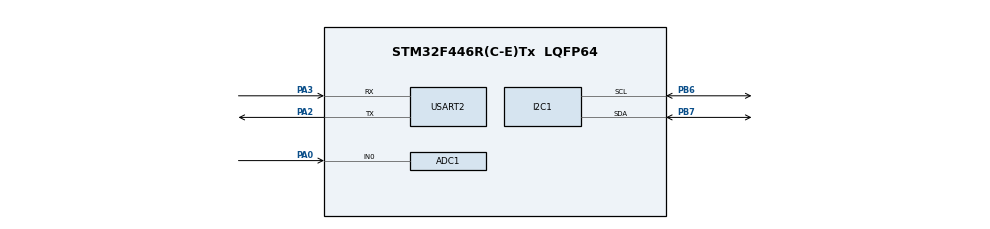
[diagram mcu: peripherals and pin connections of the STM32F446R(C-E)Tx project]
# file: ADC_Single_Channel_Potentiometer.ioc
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ADC1.Channel-0\#ChannelRegularConversion=ADC_CHANNEL_0
ADC1.ClockPrescaler=ADC_CLOCK_SYNC_PCLK_DIV4
ADC1.ContinuousConvMode=ENABLE
ADC1.NbrOfConversion=1
ADC1.NbrOfConversionFlag=1
ADC1.Rank-0\#ChannelRegularConversion=1
ADC1.SamplingTime-0\#ChannelRegularConversion=ADC_SAMPLETIME_3CYCLES
ADC1.master=1
FREERTOS.Tasks01=OLEDTask,24,128,StartTask01,Default,NULL,Dynamic,NULL,NULL;VoltageTask,24,128,StartTask02,Default,NULL,Dynamic,NULL,NULL
FREERTOS.configUSE_NEWLIB_REENTRANT=1
I2C1.I2C_Mode=I2C_Fast
Mcu.Family=STM32F4
Mcu.Name=STM32F446R(C-E)Tx
Mcu.Package=LQFP64
NVIC.PriorityGroup=NVIC_PRIORITYGROUP_4
NVIC.TIM1_UP_TIM10_IRQn=true\:15\:0\:false\:false\:true\:false\:false\:true\:true
NVIC.TimeBase=TIM1_UP_TIM10_IRQn
NVIC.TimeBaseIP=TIM1
PA0-WKUP.Signal=ADCx_IN0
PA13.Mode=Serial_Wire
PA13.Signal=SYS_JTMS-SWDIO
PA14.Mode=Serial_Wire
PA14.Signal=SYS_JTCK-SWCLK
PA2.Mode=Asynchronous
PA2.Signal=USART2_TX
PA3.Mode=Asynchronous
PA3.Signal=USART2_RX
PB6.Mode=I2C
PB6.Signal=I2C1_SCL
PB7.Mode=I2C
PB7.Signal=I2C1_SDA
PC14-OSC32_IN.Mode=LSE-External-Oscillator
PC14-OSC32_IN.Signal=RCC_OSC32_IN
PC15-OSC32_OUT.Mode=LSE-External-Oscillator
PC15-OSC32_OUT.Signal=RCC_OSC32_OUT
PH0-OSC_IN.Mode=HSE-External-Clock-Source
PH0-OSC_IN.Signal=RCC_OSC_IN
PH1-OSC_OUT.Mode=HSE-External-Clock-Source
PH1-OSC_OUT.Signal=RCC_OSC_OUT
ProjectManager.HeapSize=0x200
ProjectManager.StackSize=0x400
ProjectManager.TargetToolchain=STM32CubeIDE
RCC.48MHZClocksFreq_Value=84000000
RCC.AHBFreq_Value=64000000
RCC.APB1CLKDivider=RCC_HCLK_DIV2
RCC.APB1Freq_Value=32000000
RCC.APB1TimFreq_Value=64000000
RCC.APB2Freq_Value=64000000
RCC.APB2TimFreq_Value=64000000
RCC.CortexFreq_Value=64000000
RCC.FLatency-AdvancedSettings=FLASH_LATENCY_2
RCC.HCLKFreq_Value=64000000
RCC.HSE_VALUE=8000000
RCC.HSI_VALUE=16000000
RCC.PLLM=8
RCC.PLLN=64
RCC.SYSCLKFreq_VALUE=64000000
RCC.SYSCLKSource=RCC_SYSCLKSOURCE_PLLCLK
RCC.USBFreq_Value=64000000
RCC.VCOOutputFreq_Value=128000000
SH.ADCx_IN0.0=ADC1_IN0,IN0
USART2.VirtualMode=VM_ASYNC
VP_FREERTOS_VS_CMSIS_V2.Mode=CMSIS_V2
VP_SYS_VS_tim1.Mode=TIM1
board=NUCLEO-F446RE

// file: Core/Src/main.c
/* USER CODE BEGIN Header */
/**
  ******************************************************************************
  * @file           : main.c
  * @brief          : Main program body
  ******************************************************************************
  * @attention
  *
  * Copyright (c) 2024 STMicroelectronics.
  * All rights reserved.
  *
  * This software is licensed under terms that can be found in the LICENSE file
  * in the root directory of this software component.
  * If no LICENSE file comes with this software, it is provided AS-IS.
  *
  ******************************************************************************
  */
/* USER CODE END Header */
#include "main.h"
#include "cmsis_os.h"

/* USER CODE BEGIN Includes */
#include "task.h"
#include "stdio.h"
#include "string.h"
#include "fonts.h"
#include "ssd1306.h"
#include "semphr.h"

/* USER CODE END Includes */

ADC_HandleTypeDef hadc1;

I2C_HandleTypeDef hi2c1;

UART_HandleTypeDef huart2;

/* Definitions for adcTask */
osThreadId_t adcTaskHandle;
const osThreadAttr_t adcTask_attributes = {
  .name = "adcTask",
  .stack_size = 128 * 4,
  .priority = (osPriority_t) osPriorityNormal,
};
/* Definitions for oledTask */
osThreadId_t oledTaskHandle;
const osThreadAttr_t oledTask_attributes = {
  .name = "oledTask",
  .stack_size = 128 * 4,
  .priority = (osPriority_t) osPriorityNormal,
};

//Declare semaphore variables
SemaphoreHandle_t xBinarySemaphore1;
SemaphoreHandle_t xBinarySemaphore2;

void SystemClock_Config(void);
static void MX_GPIO_Init(void);
static void MX_USART2_UART_Init(void);
static void MX_ADC1_Init(void);
static void MX_I2C1_Init(void);
void StartTask01(void *argument);
void StartTask02(void *argument);

/* USER CODE BEGIN 0 */
uint32_t sensorValue = 0;
float fvoltage = 0;
char msg[100];

int uart2_write(int ch)
{
	/*Make sure the transmit data register is empty*/
	while(!(USART2->SR & USART_SR_TXE)){}

	 /*Write to transmit data register*/
	USART2->DR	=  (ch & 0xFF);
	return ch;
}

int __io_putchar(int ch)
{
	uart2_write(ch);
	return ch;
}

/* USER CODE END 0 */

int main(void)
{

  /* MCU Configuration--------------------------------------------------------*/

  /* Reset of all peripherals, Initializes the Flash interface and the Systick. */
  HAL_Init();

  /* Configure the system clock */
  SystemClock_Config();

  /* Initialize all configured peripherals */
  MX_GPIO_Init();
  MX_USART2_UART_Init();
  MX_ADC1_Init();
  MX_I2C1_Init();
  /* USER CODE BEGIN 2 */

  HAL_ADC_Start(&hadc1);

  SSD1306_Init();

  /* USER CODE END 2 */

  //Enter binary semapohores
  xBinarySemaphore1= xSemaphoreCreateBinary();
  xBinarySemaphore2 = xSemaphoreCreateBinary();

  xSemaphoreGive(xBinarySemaphore1);
//  xSemaphoreGive(xBinarySemaphore2);

  /* Init scheduler */
  osKernelInitialize();

  /* Create the semaphores(s) */

  /* Create the thread(s) */
  /* creation of adcTask */
  TaskHandle_t xHandle = NULL;
  TaskHandle_t xHandle2 = NULL;

  adcTaskHandle = xTaskCreate(StartTask01, "adcTask", 128 * 4, (void *) 1, 2, &xHandle);

  /* creation of oledTask */

  oledTaskHandle = xTaskCreate(StartTask02, "oledtask", 128 * 4, (void *)1, 2, &xHandle2);

  /* Start scheduler */
  osKernelStart();

  /* We should never get here as control is now taken by the scheduler */
  /* Infinite loop */
  while (1)
  {

  }
}

void SystemClock_Config(void)
{
  RCC_OscInitTypeDef RCC_OscInitStruct = {0};
  RCC_ClkInitTypeDef RCC_ClkInitStruct = {0};

  /** Configure the main internal regulator output voltage
  */
  __HAL_RCC_PWR_CLK_ENABLE();
  __HAL_PWR_VOLTAGESCALING_CONFIG(PWR_REGULATOR_VOLTAGE_SCALE3);

  /** Initializes the RCC Oscillators according to the specified parameters
  * in the RCC_OscInitTypeDef structure.
  */
  RCC_OscInitStruct.OscillatorType = RCC_OSCILLATORTYPE_HSI;
  RCC_OscInitStruct.HSIState = RCC_HSI_ON;
  RCC_OscInitStruct.HSICalibrationValue = RCC_HSICALIBRATION_DEFAULT;
  RCC_OscInitStruct.PLL.PLLState = RCC_PLL_ON;
  RCC_OscInitStruct.PLL.PLLSource = RCC_PLLSOURCE_HSI;
  RCC_OscInitStruct.PLL.PLLM = 16;
  RCC_OscInitStruct.PLL.PLLN = 336;
  RCC_OscInitStruct.PLL.PLLP = RCC_PLLP_DIV4;
  RCC_OscInitStruct.PLL.PLLQ = 2;
  RCC_OscInitStruct.PLL.PLLR = 2;
  if (HAL_RCC_OscConfig(&RCC_OscInitStruct) != HAL_OK)
  {
    Error_Handler();
  }

  /** Initializes the CPU, AHB and APB buses clocks
  */
  RCC_ClkInitStruct.ClockType = RCC_CLOCKTYPE_HCLK|RCC_CLOCKTYPE_SYSCLK
                              |RCC_CLOCKTYPE_PCLK1|RCC_CLOCKTYPE_PCLK2;
  RCC_ClkInitStruct.SYSCLKSource = RCC_SYSCLKSOURCE_PLLCLK;
  RCC_ClkInitStruct.AHBCLKDivider = RCC_SYSCLK_DIV1;
  RCC_ClkInitStruct.APB1CLKDivider = RCC_HCLK_DIV2;
  RCC_ClkInitStruct.APB2CLKDivider = RCC_HCLK_DIV1;

  if (HAL_RCC_ClockConfig(&RCC_ClkInitStruct, FLASH_LATENCY_2) != HAL_OK)
  {
    Error_Handler();
  }
}

static void MX_ADC1_Init(void)
{

  ADC_ChannelConfTypeDef sConfig = {0};

  /** Configure the global features of the ADC (Clock, Resolution, Data Alignment and number of conversion)
  */
  hadc1.Instance = ADC1;
  hadc1.Init.ClockPrescaler = ADC_CLOCK_SYNC_PCLK_DIV4;
  hadc1.Init.Resolution = ADC_RESOLUTION_12B;
  hadc1.Init.ScanConvMode = DISABLE;
  hadc1.Init.ContinuousConvMode = DISABLE;
  hadc1.Init.DiscontinuousConvMode = DISABLE;
  hadc1.Init.ExternalTrigConvEdge = ADC_EXTERNALTRIGCONVEDGE_NONE;
  hadc1.Init.ExternalTrigConv = ADC_SOFTWARE_START;
  hadc1.Init.DataAlign = ADC_DATAALIGN_RIGHT;
  hadc1.Init.NbrOfConversion = 1;
  hadc1.Init.DMAContinuousRequests = DISABLE;
  hadc1.Init.EOCSelection = ADC_EOC_SINGLE_CONV;
  if (HAL_ADC_Init(&hadc1) != HAL_OK)
  {
    Error_Handler();
  }

  /** Configure for the selected ADC regular channel its corresponding rank in the sequencer and its sample time.
  */
  sConfig.Channel = ADC_CHANNEL_0;
  sConfig.Rank = 1;
  sConfig.SamplingTime = ADC_SAMPLETIME_3CYCLES;
  if (HAL_ADC_ConfigChannel(&hadc1, &sConfig) != HAL_OK)
  {
    Error_Handler();
  }

}

static void MX_I2C1_Init(void)
{

  hi2c1.Instance = I2C1;
  hi2c1.Init.ClockSpeed = 400000;
  hi2c1.Init.DutyCycle = I2C_DUTYCYCLE_2;
  hi2c1.Init.OwnAddress1 = 0;
  hi2c1.Init.AddressingMode = I2C_ADDRESSINGMODE_7BIT;
  hi2c1.Init.DualAddressMode = I2C_DUALADDRESS_DISABLE;
  hi2c1.Init.OwnAddress2 = 0;
  hi2c1.Init.GeneralCallMode = I2C_GENERALCALL_DISABLE;
  hi2c1.Init.NoStretchMode = I2C_NOSTRETCH_DISABLE;
  if (HAL_I2C_Init(&hi2c1) != HAL_OK)
  {
    Error_Handler();
  }

}

static void MX_USART2_UART_Init(void)
{

  huart2.Instance = USART2;
  huart2.Init.BaudRate = 115200;
  huart2.Init.WordLength = UART_WORDLENGTH_8B;
  huart2.Init.StopBits = UART_STOPBITS_1;
  huart2.Init.Parity = UART_PARITY_NONE;
  huart2.Init.Mode = UART_MODE_TX_RX;
  huart2.Init.HwFlowCtl = UART_HWCONTROL_NONE;
  huart2.Init.OverSampling = UART_OVERSAMPLING_16;
  if (HAL_UART_Init(&huart2) != HAL_OK)
  {
    Error_Handler();
  }

}

static void MX_GPIO_Init(void)
{
  GPIO_InitTypeDef GPIO_InitStruct = {0};

  /* GPIO Ports Clock Enable */
  __HAL_RCC_GPIOC_CLK_ENABLE();
  __HAL_RCC_GPIOH_CLK_ENABLE();
  __HAL_RCC_GPIOA_CLK_ENABLE();
  __HAL_RCC_GPIOB_CLK_ENABLE();

  /*Configure GPIO pin Output Level */
  HAL_GPIO_WritePin(LD2_GPIO_Port, LD2_Pin, GPIO_PIN_RESET);

  /*Configure GPIO pin : B1_Pin */
  GPIO_InitStruct.Pin = B1_Pin;
  GPIO_InitStruct.Mode = GPIO_MODE_IT_FALLING;
  GPIO_InitStruct.Pull = GPIO_NOPULL;
  HAL_GPIO_Init(B1_GPIO_Port, &GPIO_InitStruct);

  /*Configure GPIO pin : LD2_Pin */
  GPIO_InitStruct.Pin = LD2_Pin;
  GPIO_InitStruct.Mode = GPIO_MODE_OUTPUT_PP;
  GPIO_InitStruct.Pull = GPIO_NOPULL;
  GPIO_InitStruct.Speed = GPIO_SPEED_FREQ_LOW;
  HAL_GPIO_Init(LD2_GPIO_Port, &GPIO_InitStruct);

}

/* USER CODE BEGIN StartTask01 */
/**
  * @brief  Function implementing the adcTask thread.
  * @param  argument: Not used
  * @retval None
  */
/* USER CODE END StartTask01 */
void StartTask01(void *argument)
{
  /* USER CODE BEGIN 5 */
  /* Infinite loop */
  for(;;)
  {
	  /*1. Start ADC */
    if( xSemaphoreTake( xBinarySemaphore1, ( TickType_t ) 100 ) == pdTRUE )
    {
      HAL_ADC_Start(&hadc1);

      /* Poll for conversion */
      HAL_ADC_PollForConversion(&hadc1,1);

      /* Get conversion */
      sensorValue = HAL_ADC_GetValue(&hadc1);
      fvoltage = (float)sensorValue * (3.3/4095.0);

      sprintf(msg, "%.1f V\r\n", fvoltage); //One digit after comma

      xSemaphoreGive(xBinarySemaphore2);
    }
  }
  /* USER CODE END 5 */
}

/* USER CODE BEGIN StartTask01 */
/**
* @brief Function implementing the oledTask thread.
* @param argument: Not used
* @retval None
*/
/* USER CODE END StartTask01 */
void StartTask02(void *argument)
{
  /* USER CODE BEGIN StartTask01 */
  /* Infinite loop */
  for(;;)
  {
    // Try to take the semaphore xBinarySemaphore2. Wait for up to 100 ticks.
	 	 if( xSemaphoreTake( xBinarySemaphore2, ( TickType_t ) 100 ) == pdTRUE )
     {
        SSD1306_GotoXY (0, 30);

        HAL_UART_Transmit(&huart2, (uint8_t*)msg, strlen(msg), HAL_MAX_DELAY); // Transmit the 'msg' string via UART

        SSD1306_Puts(msg, &Font_16x26, 1); // Display 'msg' on the OLED with specified font and size

        SSD1306_UpdateScreen(); // Refresh the OLED display to show the new text

        xSemaphoreGive(xBinarySemaphore1);
     }
  }
  /* USER CODE END StartTask01 */
}

void HAL_TIM_PeriodElapsedCallback(TIM_HandleTypeDef *htim)
{
  if (htim->Instance == TIM6) {
    HAL_IncTick();
  }
}

void Error_Handler(void)
{
  __disable_irq();
  while (1)
  {
  }
}
